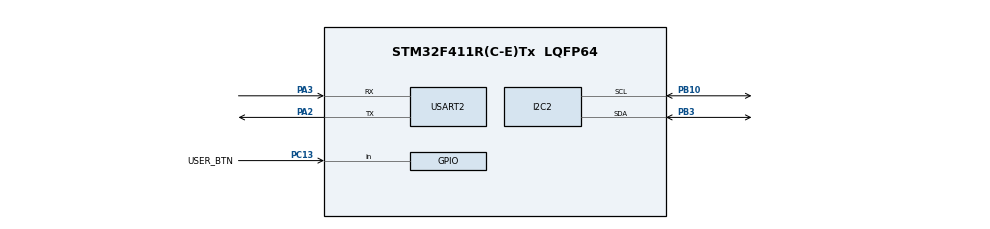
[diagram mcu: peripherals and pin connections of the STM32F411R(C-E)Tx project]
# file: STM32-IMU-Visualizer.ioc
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FREERTOS.Tasks01=defaultTask,24,256,StartDefaultTask,Default,NULL,Dynamic,NULL,NULL;buttonTask,24,128,StartButtonTask,Default,NULL,Dynamic,NULL,NULL
Mcu.Family=STM32F4
Mcu.Name=STM32F411R(C-E)Tx
Mcu.Package=LQFP64
NVIC.PriorityGroup=NVIC_PRIORITYGROUP_4
NVIC.TIM1_UP_TIM10_IRQn=true\:15\:0\:false\:false\:true\:false\:false\:true\:true
NVIC.TimeBase=TIM1_UP_TIM10_IRQn
NVIC.TimeBaseIP=TIM1
NVIC.USART2_IRQn=true\:5\:0\:false\:false\:true\:true\:true\:true\:true
PA13.Mode=Serial_Wire
PA13.Signal=SYS_JTMS-SWDIO
PA14.Mode=Serial_Wire
PA14.Signal=SYS_JTCK-SWCLK
PA2.Mode=Asynchronous
PA2.Signal=USART2_TX
PA3.Mode=Asynchronous
PA3.Signal=USART2_RX
PB10.Mode=I2C
PB10.Signal=I2C2_SCL
PB3.Mode=I2C
PB3.Signal=I2C2_SDA
PC13-ANTI_TAMP.GPIO_Label=USER_BTN
PC13-ANTI_TAMP.Signal=GPIO_Input
PH0\ -\ OSC_IN.Mode=HSE-External-Oscillator
PH0\ -\ OSC_IN.Signal=RCC_OSC_IN
PH1\ -\ OSC_OUT.Mode=HSE-External-Oscillator
PH1\ -\ OSC_OUT.Signal=RCC_OSC_OUT
ProjectManager.HeapSize=0x200
ProjectManager.StackSize=0x400
ProjectManager.TargetToolchain=CMake
RCC.48MHZClocksFreq_Value=50000000
RCC.AHBFreq_Value=100000000
RCC.APB1CLKDivider=RCC_HCLK_DIV2
RCC.APB1Freq_Value=50000000
RCC.APB1TimFreq_Value=100000000
RCC.APB2Freq_Value=100000000
RCC.APB2TimFreq_Value=100000000
RCC.CortexFreq_Value=100000000
RCC.HCLKFreq_Value=100000000
RCC.HSE_VALUE=25000000
RCC.HSI_VALUE=16000000
RCC.LSE_VALUE=32768
RCC.PLLM=8
RCC.PLLN=100
RCC.SYSCLKFreq_VALUE=100000000
RCC.SYSCLKSource=RCC_SYSCLKSOURCE_PLLCLK
RCC.VCOOutputFreq_Value=200000000
USART2.VirtualMode=VM_ASYNC
VP_FREERTOS_VS_CMSIS_V2.Mode=CMSIS_V2
VP_SYS_VS_tim1.Mode=TIM1
board=custom

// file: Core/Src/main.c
/* USER CODE BEGIN Header */
/**
  ******************************************************************************
  * @file           : main.c
  * @brief          : Main program body
  ******************************************************************************
  * @attention
  *
  * Copyright (c) 2024 STMicroelectronics.
  * All rights reserved.
  *
  * This software is licensed under terms that can be found in the LICENSE file
  * in the root directory of this software component.
  * If no LICENSE file comes with this software, it is provided AS-IS.
  *
  ******************************************************************************
  */
/* USER CODE END Header */
#include "main.h"
#include "cmsis_os.h"

/* USER CODE BEGIN Includes */
#include <semphr.h>
#include "bmi160.h"
#include "routine.h"
#include "lcd1602_i2c_lib.h"
/* USER CODE END Includes */

/* USER CODE BEGIN PD */
/*! bmi160 shuttle id */
#define BMI160_SHUTTLE_ID     0x38

/*! bmi160 Device address */
#define BMI160_ADDR       0x69
#define LCD_ADDR (0x27 << 1)

#define ACCEL_CONVERSION 0.000598  // ±2g (м/с²/LSB)
#define GYRO_CONVERSION  0.00381   // ±125°/с (°/с/LSB)

// SDA - PB7  (LEFT)

/* USER CODE END PD */

I2C_HandleTypeDef hi2c2;
UART_HandleTypeDef huart2;

/* Definitions for defaultTask */
osThreadId_t defaultTaskHandle;
const osThreadAttr_t defaultTask_attributes = {
  .name = "defaultTask",
  .stack_size = 2056,
  .priority = (osPriority_t) osPriorityRealtime7,
};
/* Definitions for buttonTask */
osThreadId_t buttonTaskHandle;
const osThreadAttr_t buttonTask_attributes = {
  .name = "buttonTask",
  .stack_size = 128 * 4,
  .priority = (osPriority_t) osPriorityLow,
};
/* USER CODE BEGIN PV */

I2C_LCD_HandleTypeDef lcd1;
struct bmi160_dev sensor;
SemaphoreHandle_t sensorSemaphore;
StaticSemaphore_t displayStateMutexBuffer;
SemaphoreHandle_t displayStateMutex;
static EDisplayState displayState = All;

/* USER CODE END PV */

void SystemClock_Config(void);
static void MX_GPIO_Init(void);
static void MX_USART2_UART_Init(void);
static void MX_I2C2_Init(void);
void StartDefaultTask(void *argument);
void StartButtonTask(void *argument);

/* USER CODE BEGIN 0 */

int8_t i2c_write(uint8_t dev_addr, uint8_t reg_addr, uint8_t *data, uint16_t len) {
    return HAL_I2C_Mem_Write(&hi2c2, dev_addr << 1, reg_addr, I2C_MEMADD_SIZE_8BIT, data, len, HAL_MAX_DELAY) == HAL_OK ? 0 : -1;
}

int8_t i2c_read(uint8_t dev_addr, uint8_t reg_addr, uint8_t *data, uint16_t len) {
    return HAL_I2C_Mem_Read(&hi2c2, dev_addr << 1, reg_addr, I2C_MEMADD_SIZE_8BIT, data, len, HAL_MAX_DELAY) == HAL_OK ? 0 : -1;
}

void displayAcceleration(float accelX, float accelY, float accelZ) {
    char line[16];
    float totalAcceleration = sqrt(accelX * accelX + accelY * accelY + accelZ * accelZ);

    // min max вираховуємо
    float maxAccel = fmax(fmax(fabs(accelX), fabs(accelY)), fabs(accelZ));
    float minAccel = fmin(fmin(fabs(accelX), fabs(accelY)), fabs(accelZ));

    const char maxAxis = maxAccel == fabs(accelX) ? 'X' : maxAccel == fabs(accelY) ? 'Y' : 'Z';
    const char minAxis =  minAccel == fabs(accelX) ? 'X' : minAccel == fabs(accelY) ? 'Y' : 'Z';

    lcd_clear(&lcd1);
    lcd_gotoxy(&lcd1, 0, 0);
    switch(displayState) {
      case Min:
          snprintf(line, sizeof(line), "> Min. Axis: %c", minAxis);
          lcd_puts(&lcd1, line);
          lcd_gotoxy(&lcd1, 0, 1);
          snprintf(line, sizeof(line), "Value: %.4f", minAccel);
          lcd_puts(&lcd1, line);
        break;

      case Max:
          snprintf(line, sizeof(line), "> Max. Axis: %c", maxAxis);
          lcd_puts(&lcd1, line);
          lcd_gotoxy(&lcd1, 0, 1);
          snprintf(line, sizeof(line), "Value: %.4f", maxAccel);
          lcd_puts(&lcd1, line);
        break;
      case All:
        lcd_puts(&lcd1, " Min  Max  Total");
        lcd_gotoxy(&lcd1, 0, 1);
        snprintf(line, sizeof(line), "%c%.1f %c%.1f %.1f",minAxis, minAccel, maxAxis, maxAccel, totalAcceleration);
        lcd_puts(&lcd1, line);
        break;
      case Total:
          lcd_puts(&lcd1, "> Total accel.");
          lcd_gotoxy(&lcd1, 0, 1);
          snprintf(line, sizeof(line), "Value: %.4f", totalAcceleration);
          lcd_puts(&lcd1, line);
        break;
    }

}

void process_sensor_data(struct bmi160_sensor_data accel, struct bmi160_sensor_data gyro) {
    float accelX = accel.x * ACCEL_CONVERSION;  // м/с²
    float accelY = accel.y * ACCEL_CONVERSION;  // м/с²
    float accelZ = accel.z * ACCEL_CONVERSION;  // м/с²

  /*  float gyroX = gyro.x * GYRO_CONVERSION;  // °/с
    float gyroY = gyro.y * GYRO_CONVERSION;  // °/с
    float gyroZ = gyro.z * GYRO_CONVERSION;  // °/с */

    // print to lcd
    // 1. Maximum acceleration (and axis);
    // 2. Minimum acceleration (and axis);
    // 3. Total acceleration vector
    displayAcceleration(accelX, accelY, accelZ);

    uart_printf("{ \"Ax\": %d, \"Ay\":%d, \"Az\":%d, \"Gx\":%d, \"Gy\":%d, \"Gz\":%d }",
                    accel.x, accel.y, accel.z, gyro.x, gyro.y, gyro.z);
}

void BMI160_Init(void)
{
  int8_t rslt;

  sensor.write = i2c_write;
  sensor.read = i2c_read;
  sensor.delay_ms = HAL_Delay;

  /* set correct i2c address */
  sensor.id = BMI160_ADDR;
  sensor.intf = BMI160_I2C_INTF;

  rslt = bmi160_init(&sensor);

  if (bmi160_init(&sensor) != BMI160_OK)
  {
    uart_printf("BMI160 initialization failed");
    exit(rslt);
  }

  sensor.accel_cfg.odr = BMI160_ACCEL_ODR_1600HZ;
  sensor.accel_cfg.range = BMI160_ACCEL_RANGE_2G; // ±2g
  sensor.accel_cfg.bw = BMI160_ACCEL_BW_NORMAL_AVG4;

  /* Select the power mode of accelerometer sensor */
  sensor.accel_cfg.power = BMI160_ACCEL_NORMAL_MODE;

  /* Select the Output data rate, range of Gyroscope sensor */
  sensor.gyro_cfg.odr = BMI160_GYRO_ODR_3200HZ;
  sensor.gyro_cfg.range = BMI160_GYRO_RANGE_125_DPS; // ±125°/с
  sensor.gyro_cfg.bw = BMI160_GYRO_BW_NORMAL_MODE;

  /* Select the power mode of Gyroscope sensor */
  sensor.gyro_cfg.power = BMI160_GYRO_NORMAL_MODE;

  rslt = bmi160_set_sens_conf(&sensor);
  if (rslt != BMI160_OK)
  {
    uart_printf("Error setting sensor configuration: %d", rslt);
    exit(rslt);
  }
}

void LCD1602_Init(void)
{
  lcd1.hi2c = &hi2c2;     // hi2c2 is your I2C handler
  lcd1.address = LCD_ADDR;    // I2C address for the first LCD
  lcd_init(&lcd1);        // Initialize the first LCD
  lcd_clear(&lcd1);
}

void initResources() {
    BMI160_Init();
    LCD1602_Init();
    sensorSemaphore = xSemaphoreCreateMutex();
    displayStateMutex = xSemaphoreCreateMutexStatic(&displayStateMutexBuffer);
}

/* USER CODE END 0 */

int main(void)
{

  /* MCU Configuration--------------------------------------------------------*/

  /* Reset of all peripherals, Initializes the Flash interface and the Systick. */
  HAL_Init();

  /* Configure the system clock */
  SystemClock_Config();

  /* Initialize all configured peripherals */
  MX_GPIO_Init();
  MX_USART2_UART_Init();
  MX_I2C2_Init();
  /* USER CODE BEGIN 2 */
  setOutputUart(&huart2);
  I2C_Scan(&hi2c2);
  initResources();
  /* USER CODE END 2 */

  /* Init scheduler */
  osKernelInitialize();

  /* Create the thread(s) */
  /* creation of defaultTask */
  defaultTaskHandle = osThreadNew(StartDefaultTask, NULL, &defaultTask_attributes);

  /* creation of buttonTask */
  buttonTaskHandle = osThreadNew(StartButtonTask, NULL, &buttonTask_attributes);

  /* Start scheduler */
  osKernelStart();

  /* We should never get here as control is now taken by the scheduler */

  /* Infinite loop */
  while (1)
  {

  }
}

void SystemClock_Config(void)
{
  RCC_OscInitTypeDef RCC_OscInitStruct = {0};
  RCC_ClkInitTypeDef RCC_ClkInitStruct = {0};

  /** Configure the main internal regulator output voltage
  */
  __HAL_RCC_PWR_CLK_ENABLE();
  __HAL_PWR_VOLTAGESCALING_CONFIG(PWR_REGULATOR_VOLTAGE_SCALE1);

  /** Initializes the RCC Oscillators according to the specified parameters
  * in the RCC_OscInitTypeDef structure.
  */
  RCC_OscInitStruct.OscillatorType = RCC_OSCILLATORTYPE_HSI;
  RCC_OscInitStruct.HSIState = RCC_HSI_ON;
  RCC_OscInitStruct.HSICalibrationValue = RCC_HSICALIBRATION_DEFAULT;
  RCC_OscInitStruct.PLL.PLLState = RCC_PLL_NONE;
  if (HAL_RCC_OscConfig(&RCC_OscInitStruct) != HAL_OK)
  {
    Error_Handler();
  }

  /** Initializes the CPU, AHB and APB buses clocks
  */
  RCC_ClkInitStruct.ClockType = RCC_CLOCKTYPE_HCLK|RCC_CLOCKTYPE_SYSCLK
                              |RCC_CLOCKTYPE_PCLK1|RCC_CLOCKTYPE_PCLK2;
  RCC_ClkInitStruct.SYSCLKSource = RCC_SYSCLKSOURCE_HSI;
  RCC_ClkInitStruct.AHBCLKDivider = RCC_SYSCLK_DIV1;
  RCC_ClkInitStruct.APB1CLKDivider = RCC_HCLK_DIV1;
  RCC_ClkInitStruct.APB2CLKDivider = RCC_HCLK_DIV1;

  if (HAL_RCC_ClockConfig(&RCC_ClkInitStruct, FLASH_LATENCY_0) != HAL_OK)
  {
    Error_Handler();
  }
}

static void MX_I2C2_Init(void)
{

  hi2c2.Instance = I2C2;
  hi2c2.Init.ClockSpeed = 100000;
  hi2c2.Init.DutyCycle = I2C_DUTYCYCLE_2;
  hi2c2.Init.OwnAddress1 = 0;
  hi2c2.Init.AddressingMode = I2C_ADDRESSINGMODE_7BIT;
  hi2c2.Init.DualAddressMode = I2C_DUALADDRESS_DISABLE;
  hi2c2.Init.OwnAddress2 = 0;
  hi2c2.Init.GeneralCallMode = I2C_GENERALCALL_DISABLE;
  hi2c2.Init.NoStretchMode = I2C_NOSTRETCH_DISABLE;
  if (HAL_I2C_Init(&hi2c2) != HAL_OK)
  {
    Error_Handler();
  }

}

static void MX_USART2_UART_Init(void)
{

  huart2.Instance = USART2;
  huart2.Init.BaudRate = 115200;
  huart2.Init.WordLength = UART_WORDLENGTH_8B;
  huart2.Init.StopBits = UART_STOPBITS_1;
  huart2.Init.Parity = UART_PARITY_NONE;
  huart2.Init.Mode = UART_MODE_TX_RX;
  huart2.Init.HwFlowCtl = UART_HWCONTROL_NONE;
  huart2.Init.OverSampling = UART_OVERSAMPLING_16;
  if (HAL_UART_Init(&huart2) != HAL_OK)
  {
    Error_Handler();
  }

}

static void MX_GPIO_Init(void)
{
  GPIO_InitTypeDef GPIO_InitStruct = {0};

  /* GPIO Ports Clock Enable */
  __HAL_RCC_GPIOC_CLK_ENABLE();
  __HAL_RCC_GPIOH_CLK_ENABLE();
  __HAL_RCC_GPIOA_CLK_ENABLE();
  __HAL_RCC_GPIOB_CLK_ENABLE();

  /*Configure GPIO pin : USER_BTN_Pin */
  GPIO_InitStruct.Pin = USER_BTN_Pin;
  GPIO_InitStruct.Mode = GPIO_MODE_INPUT;
  GPIO_InitStruct.Pull = GPIO_NOPULL;
  HAL_GPIO_Init(USER_BTN_GPIO_Port, &GPIO_InitStruct);

}

/* USER CODE BEGIN 4 */

static int readBMI160(struct bmi160_sensor_data* accel, struct bmi160_sensor_data* gyro) {
    int8_t result = -1;
    if(xSemaphoreTake(sensorSemaphore, 0) == pdTRUE) {
        result = bmi160_get_sensor_data((BMI160_ACCEL_SEL | BMI160_GYRO_SEL), accel, gyro, &sensor);
        xSemaphoreGive(sensorSemaphore);
    }
    return result;
}

static void updateDisplayState() {
  if(xSemaphoreTake(displayStateMutex, pdMS_TO_TICKS(10)) == pdTRUE) {
    if(++displayState > Total) {
        displayState = All;
    }
    xSemaphoreGive(displayStateMutex);
}
}

/* USER CODE END 4 */

void StartDefaultTask(void *argument)
{
  /* USER CODE BEGIN 5 */
  struct bmi160_sensor_data accel;
  struct bmi160_sensor_data gyro;
  /* Infinite loop */
  for(;;)
  {
    if (readBMI160(&accel, &gyro) == 0) {
        process_sensor_data(accel, gyro);
    } else {
        uart_printf("Error reading accelerometer data");
    }

    osDelay(30);
  }
  /* USER CODE END 5 */
}

void StartButtonTask(void *argument)
{
  /* USER CODE BEGIN StartButtonTask */
  GPIO_PinState lastState = -1;
  /* Infinite loop */
  for(;;)
  {
    GPIO_PinState currentState = HAL_GPIO_ReadPin(USER_BTN_GPIO_Port, USER_BTN_Pin);
    if(currentState == GPIO_PIN_SET && lastState == GPIO_PIN_RESET) {
      updateDisplayState();
      osDelay(50);
    }

    lastState = currentState;
    osDelay(10);
  }
  /* USER CODE END StartButtonTask */
}

void HAL_TIM_PeriodElapsedCallback(TIM_HandleTypeDef *htim)
{
  if (htim->Instance == TIM1) {
    HAL_IncTick();
  }
}

void Error_Handler(void)
{
  __disable_irq();
  while (1)
  {
  }
}
